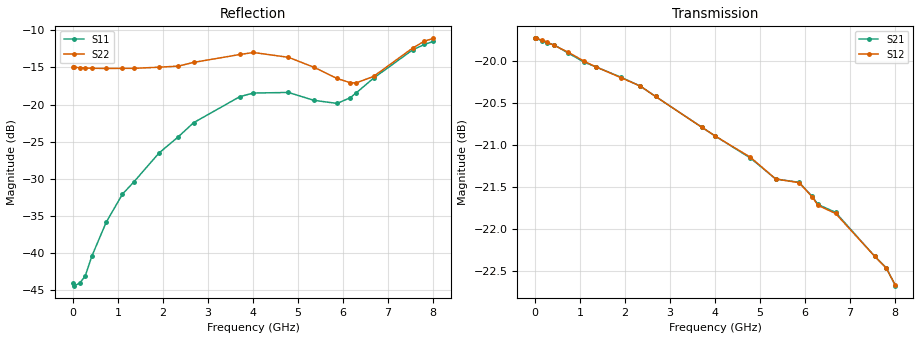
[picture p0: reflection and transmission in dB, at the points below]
! DEVICE ID: PE43712
! File Path: z:\PE43713\PE43713_CHAR_NOM_04292014\AMB\3p300\LS_ATT_18p50dB\PE43713_AMB_3p300V_3p000V_0p000V_LS_ATT_18p50dB_S2P_SN_10_A0139A.s2p
! Serial: 10
! Lot: A0139A
! Temp: 25C
! VDD: 3.300
! VSS: 0.000
! Control_Hi: 3.000
! Control_Lo: 0.000
! Attenuation Step: 18.50dB
! Port 1: RF1
! Port 2: RF2
! ThroughPath:1-2
! IDD: 0.0001464251
! ISS: -8.22e-008
#  Hz  S  RI  R  50
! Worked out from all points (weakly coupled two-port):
!   801 points, 10 MHz to 8.01 GHz, reference 50 ohm
!   highest |S21| = -19.72 dB at 10 MHz (marker M1); lowest = -22.7 dB at 8.01 GHz (marker M2)
!   lowest |S11| = -44.4 dB at 30 MHz (marker M3), VSWR 1.01, Z = 49.4 + j0.136 ohm
!   |S11| at or under -10 dB: start of sweep to end of sweep
!   |S22| runs from -17.1 to -11.1 dB; largest |S21 - S12| = 0.00039
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1e7  -0.00622 0.000564  0.1032 -0.000526  0.1032 -0.000509  -0.1789 0.00128
3e7  -0.00585 0.00138  0.1032 -0.0013  0.1032 -0.00132  -0.1783 0.00307
1.5e8  -0.00501 0.00373  0.1027 -0.00609  0.1028 -0.0061  -0.1768 0.0117
2.7e8  -0.00432 0.00547  0.102 -0.0107  0.1021 -0.0108  -0.1752 0.0187
4.2e8  -0.00398 0.00865  0.101 -0.0164  0.1009 -0.0164  -0.1732 0.0278
7.4e8  -0.00366 0.0157  0.0973 -0.0276  0.0974 -0.0277  -0.168 0.0491
1.1e9  -0.00226 0.0248  0.0919 -0.0391  0.092 -0.0392  -0.1598 0.0719
1.35e9  0.000147 0.03  0.0877 -0.0465  0.0877 -0.0465  -0.1528 0.0858
1.91e9  0.00883 0.0462  0.0762 -0.0614  0.0762 -0.0613  -0.1311 0.1209
2.34e9  0.0181 0.0578  0.0655 -0.0711  0.0655 -0.0711  -0.1108 0.1437
2.68e9  0.0269 0.0704  0.0563 -0.0769  0.0563 -0.0769  -0.0931 0.1681
3.71e9  0.039 0.1061  0.0256 -0.0877  0.0256 -0.0877  -0.0581 0.2094
4.01e9  0.0402 0.1125  0.0167 -0.0887  0.0167 -0.0887  -0.0542 0.2175
4.79e9  0.0438 0.1123  -0.00563 -0.0874  -0.00563 -0.0875  -0.0331 0.2053
5.35e9  0.0562 0.0908  -0.0201 -0.0827  -0.0201 -0.0827  -0.0126 0.1781
5.87e9  0.0769 0.0665  -0.0333 -0.0779  -0.0332 -0.0779  0.029 0.1469
6.16e9  0.0945 0.0583  -0.0408 -0.0724  -0.0407 -0.0724  0.0597 0.127
6.29e9  0.1058 0.0553  -0.0429 -0.0701  -0.0427 -0.0701  0.0757 0.1174
6.68e9  0.1413 0.0518  -0.0504 -0.0638  -0.0502 -0.0638  0.1226 0.0941
7.55e9  0.2251 0.0621  -0.0634 -0.0429  -0.0634 -0.0429  0.2228 0.0896
7.81e9  0.244 0.0697  -0.0654 -0.0374  -0.0653 -0.0375  0.2496 0.0952
8.01e9  0.2553 0.0759  -0.0658 -0.0328  -0.0658 -0.0329  0.2622 0.0956
